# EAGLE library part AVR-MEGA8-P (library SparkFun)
MICROCONTROLLER 8 Kbytes FLASH 1 kbytes SRAM 512 bytes EEPROM USART 4-channel 10 bit ADC 2-channel 8 bit ADC

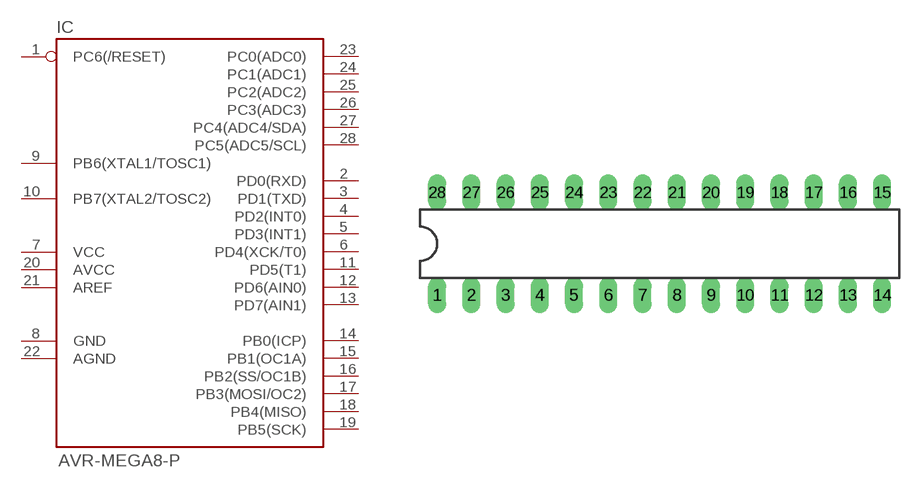
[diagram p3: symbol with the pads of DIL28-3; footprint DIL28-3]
Designator prefix IC

## AVR-MEGA8-P  [DIL28-3]
1  PC6(/RESET)
2  PD0(RXD)
3  PD1(TXD)
4  PD2(INT0)
5  PD3(INT1)
6  PD4(XCK/T0)
7  VCC
8  GND
9  PB6(XTAL1/TOSC1)
10  PB7(XTAL2/TOSC2)
11  PD5(T1)
12  PD6(AIN0)
13  PD7(AIN1)
14  PB0(ICP)
15  PB1(OC1A)
16  PB2(SS/OC1B)
17  PB3(MOSI/OC2)
18  PB4(MISO)
19  PB5(SCK)
20  AVCC
21  AREF
22  AGND
23  PC0(ADC0)
24  PC1(ADC1)
25  PC2(ADC2)
26  PC3(ADC3)
27  PC4(ADC4/SDA)
28  PC5(ADC5/SCL)

## Footprint DIL28-3 (pad centres in mm)
drill 0.813 long: 1 -13.97,-3.81; 2 -11.43,-3.81; 3 -8.89,-3.81; 4 -6.35,-3.81; 5 -3.81,-3.81; 6 -1.27,-3.81; 7 1.27,-3.81; 8 3.81,-3.81; 9 6.35,-3.81; 10 8.89,-3.81; 11 11.43,-3.81; 12 13.97,-3.81; 13 16.51,-3.81; 14 19.05,-3.81; 15 19.05,3.81; 16 16.51,3.81; 17 13.97,3.81; 18 11.43,3.81; 19 8.89,3.81; 20 6.35,3.81; 21 3.81,3.81; 22 1.27,3.81; 23 -1.27,3.81; 24 -3.81,3.81; 25 -6.35,3.81; 26 -8.89,3.81; 27 -11.43,3.81; 28 -13.97,3.81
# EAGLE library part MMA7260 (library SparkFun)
MMA7260Q Triple axis accelerometer from Freescale. Schematic element and footprint production proven. Center pad has reduced paste layer for solder short reduction. Spark Fun Electronics SKU : COM-00308

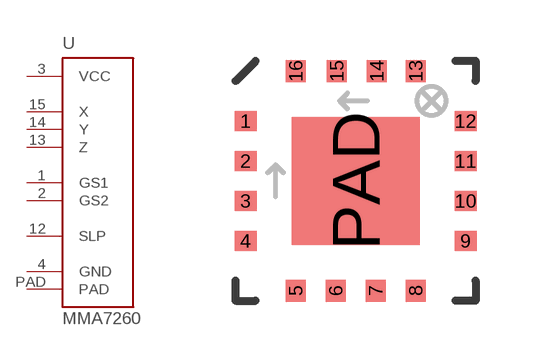
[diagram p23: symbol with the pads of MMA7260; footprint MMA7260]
Designator prefix U

## MMA7260  [MMA7260]
1  GS1
2  GS2
3  VCC
4  GND
12  SLP
13  Z
14  Y
15  X
PAD  PAD

## Footprint MMA7260 (pad centres in mm)
smd 0.55 x 0.5: 1 -2.75,1.5; 2 -2.75,0.5; 3 -2.75,-0.5; 4 -2.75,-1.5; 9 2.75,-1.5; 10 2.75,-0.5; 11 2.75,0.5; 12 2.75,1.5
smd 0.5 x 0.55: 5 -1.5,-2.75; 6 -0.5,-2.75; 7 0.5,-2.75; 8 1.5,-2.75; 13 1.5,2.75; 14 0.525,2.75; 15 -0.475,2.75; 16 -1.5,2.75
smd 3.2 x 3.2: PAD 0,0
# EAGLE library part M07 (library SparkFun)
Header 7 Standard 7-pin 0.1" header. Use with straight break away headers (SKU : PRT-00116), right angle break away headers (PRT-00553), swiss pins (PRT-00743), machine pins (PRT-00117), and female headers (PRT-00115). NOTES ON THE VARIANTS LOCK and LOCK_LONGPADS... This footprint was designed to help hold the alignment of a through-hole component (i.e. 7-pin header) while soldering it into place. You may notice that each hole has been shifted either up or down by 0.005 of an inch from it's more standard position (which is usually a perfectly straight line). This slight alteration caused the pins (the squares in the middle) to touch the edges of the holes. Because they are alternating, it causes a "brace" to hold the header in place. 0.005 has proven to be the perfect amount of "off-center" position when using our standard breakaway headers. Although looks a little odd when you look at the bare footprint, once you have a header in there, the alteration is very hard to notice. Also, if you push a header all the way into place, it is covered up entirely on the bottom side. This idea of altering the position of holes to aid alignment will be further integrated into the Sparkfun Library for other footprints. It can help hold any component with 3 or more connection pins.

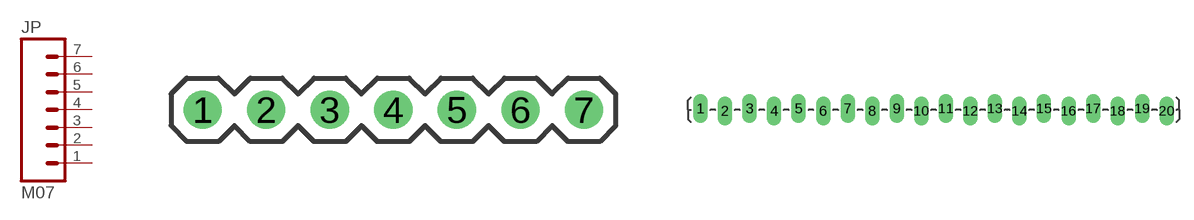
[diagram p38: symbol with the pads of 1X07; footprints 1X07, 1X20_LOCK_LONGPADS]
Designator prefix JP

## M07  [1X07]
1  1  pas
2  2  pas
3  3  pas
4  4  pas
5  5  pas
6  6  pas
7  7  pas

## M07LOCK_LONGPADS  [1X20_LOCK_LONGPADS]
Pads as for 1X07

## M07LOCK  [1X07_LOCK]
Pads as for 1X07

## Footprint 1X07 (pad centres in mm)
drill 1.016 round: 1 0,0; 2 2.54,0; 3 5.08,0; 4 7.62,0; 5 10.16,0; 6 12.7,0; 7 15.24,0

## Footprint 1X20_LOCK_LONGPADS (pad centres in mm)
drill 1.016 long: 1 0,0.127; 2 2.54,-0.127; 3 5.08,0.127; 4 7.62,-0.127; 5 10.16,0.127; 6 12.7,-0.127; 7 15.24,0.127; 8 17.78,-0.127; 9 20.32,0.127; 10 22.86,-0.127; 11 25.4,0.127; 12 27.94,-0.127; 13 30.48,0.127; 14 33.02,-0.127; 15 35.56,0.127; 16 38.1,-0.127; 17 40.64,0.127; 18 43.18,-0.127; 19 45.72,0.127; 20 48.26,-0.127

## Footprint 1X07_LOCK (pad centres in mm)
drill 1.016 round: 1 0,0.127; 2 2.54,-0.127; 3 5.08,0.127; 4 7.62,-0.127; 5 10.16,0.127; 6 12.7,-0.127; 7 15.24,0.127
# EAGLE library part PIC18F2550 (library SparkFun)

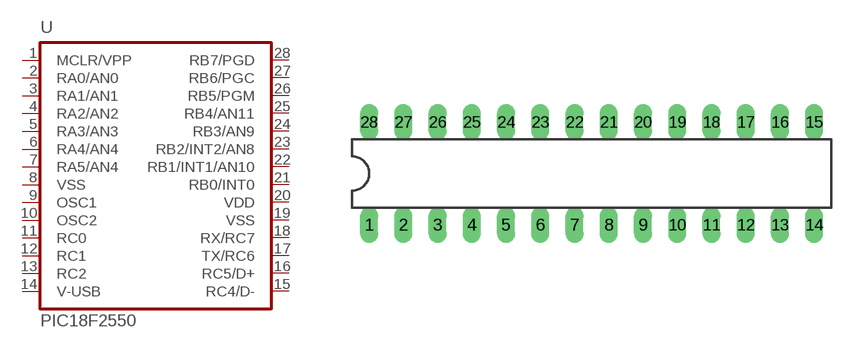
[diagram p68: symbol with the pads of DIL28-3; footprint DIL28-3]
Designator prefix -

## PIC18F2550  [DIL28-3]
1  MCLR/VPP
2  RA0/AN0
3  RA1/AN1
4  RA2/AN2
5  RA3/AN3
6  RA4/AN4
7  RA5/AN4
8  VSS  pwr
9  OSC1
10  OSC2
11  RC0
12  RC1
13  RC2
14  V-USB
15  RC4/D-
16  RC5/D+
17  TX/RC6
18  RX/RC7  in
19  VSS  pwr
20  VDD  pwr
21  RB0/INT0
22  RB1/INT1/AN10
23  RB2/INT2/AN8
24  RB3/AN9
25  RB4/AN11
26  RB5/PGM
27  RB6/PGC
28  RB7/PGD

## Footprint DIL28-3 (pad centres in mm)
drill 0.813 long: 1 -13.97,-3.81; 2 -11.43,-3.81; 3 -8.89,-3.81; 4 -6.35,-3.81; 5 -3.81,-3.81; 6 -1.27,-3.81; 7 1.27,-3.81; 8 3.81,-3.81; 9 6.35,-3.81; 10 8.89,-3.81; 11 11.43,-3.81; 12 13.97,-3.81; 13 16.51,-3.81; 14 19.05,-3.81; 15 19.05,3.81; 16 16.51,3.81; 17 13.97,3.81; 18 11.43,3.81; 19 8.89,3.81; 20 6.35,3.81; 21 3.81,3.81; 22 1.27,3.81; 23 -1.27,3.81; 24 -3.81,3.81; 25 -6.35,3.81; 26 -8.89,3.81; 27 -11.43,3.81; 28 -13.97,3.81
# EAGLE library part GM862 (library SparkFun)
GM862 Cellular Module with GPS Proven layout and schematic for GM862 cellular module with SiRF III GPS. Spark Fun Electronics SKU : CEL-07917

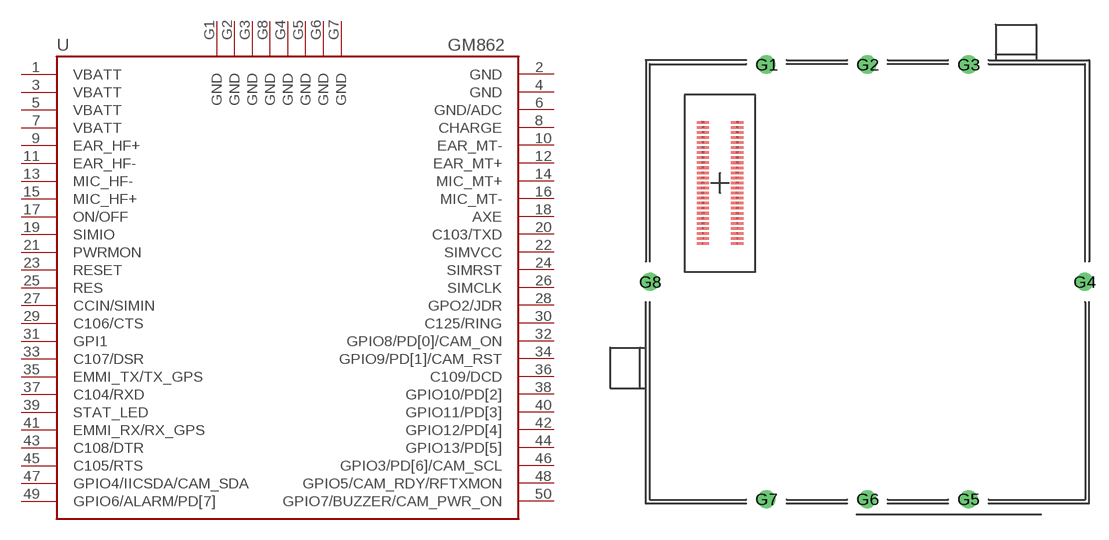
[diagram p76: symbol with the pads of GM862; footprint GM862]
Designator prefix -

## GM862GND  [GM862]
1  VBATT  pwr
2  GND  pwr
3  VBATT  pwr
4  GND  pwr
5  VBATT  pwr
6  GND/ADC  pwr
7  VBATT  pwr
8  CHARGE  in
9  EAR_HF+  out
10  EAR_MT-  out
11  EAR_HF-  out
12  EAR_MT+  out
13  MIC_HF-  in
14  MIC_MT+  in
15  MIC_HF+  in
16  MIC_MT-  in
17  ON/OFF  in
18  AXE  in
19  SIMIO
20  C103/TXD  in
21  PWRMON  out
22  SIMVCC  pwr
23  RESET  in
24  SIMRST  out
25  RES
26  SIMCLK  out
27  CCIN/SIMIN
28  GPO2/JDR  out
29  C106/CTS
30  C125/RING  out
31  GPI1  in
32  GPIO8/PD[0]/CAM_ON
33  C107/DSR  out
34  GPIO9/PD[1]/CAM_RST
35  EMMI_TX/TX_GPS  out
36  C109/DCD  out
37  C104/RXD  out
38  GPIO10/PD[2]
39  STAT_LED  out
40  GPIO11/PD[3]
41  EMMI_RX/RX_GPS  in
42  GPIO12/PD[4]
43  C108/DTR  in
44  GPIO13/PD[5]
45  C105/RTS  in
46  GPIO3/PD[6]/CAM_SCL
47  GPIO4/IICSDA/CAM_SDA
48  GPIO5/CAM_RDY/RFTXMON
49  GPIO6/ALARM/PD[7]
50  GPIO7/BUZZER/CAM_PWR_ON
G1  GND  pwr
G2  GND  pwr
G3  GND  pwr
G4  GND  pwr
G5  GND  pwr
G6  GND  pwr
G7  GND  pwr
G8  GND  pwr

## Footprint GM862 (pad centres in mm)
smd 1.2 x 0.25: 1 -12.898,3.788; 2 -16.298,3.792; 3 -12.898,4.288; 4 -16.298,4.292; 5 -12.898,4.788; 6 -16.298,4.792; 7 -12.898,5.288; 8 -16.298,5.292; 9 -12.898,5.788; 10 -16.298,5.792; 11 -12.899,6.287; 12 -16.298,6.292; 13 -12.898,6.788; 14 -16.298,6.792; 15 -12.898,7.288; 16 -16.298,7.292; 17 -12.898,7.788; 18 -16.298,7.792; 19 -12.898,8.288; 20 -16.298,8.292; 21 -12.898,8.788; 22 -16.298,8.792; 23 -12.898,9.288; 24 -16.298,9.292; 25 -12.898,9.788; 26 -16.298,9.792; 27 -12.898,10.288; 28 -16.298,10.292; 29 -12.898,10.788; 30 -16.298,10.792; 31 -12.898,11.288; 32 -16.298,11.292; 33 -12.898,11.788; 34 -16.298,11.792; 35 -12.898,12.288; 36 -16.298,12.292; 37 -12.898,12.788; 38 -16.298,12.792; 39 -12.898,13.288; 40 -16.298,13.292; 41 -12.898,13.788; 42 -16.298,13.792; 43 -12.898,14.288; 44 -16.298,14.292; 45 -12.898,14.788; 46 -16.298,14.792; 47 -12.898,15.288; 48 -16.298,15.292; 49 -12.898,15.788; 50 -16.298,15.792
drill 1.2 round: G1 -10,21.5; G2 0,21.5; G3 10,21.5; G4 21.5,0; G5 10,-21.5; G6 0,-21.5; G7 -10,-21.5; G8 -21.5,0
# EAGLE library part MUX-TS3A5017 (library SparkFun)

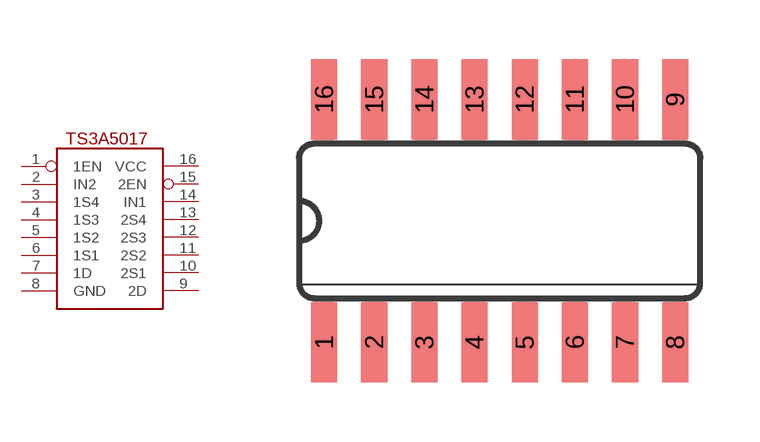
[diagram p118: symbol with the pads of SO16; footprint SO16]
Designator prefix -

## MUX-TS3A5017  [SO16]
1  1EN
2  IN2
3  1S4
4  1S3
5  1S2
6  1S1
7  1D
8  GND
9  2D
10  2S1
11  2S2
12  2S3
13  2S4
14  IN1
15  2EN
16  VCC

## Footprint SO16 (pad centres in mm)
Small Outline package 150 mil
smd 0.66 x 2.032: 1 -4.445,-3.073; 2 -3.175,-3.073; 3 -1.905,-3.073; 4 -0.635,-3.073; 5 0.635,-3.073; 6 1.905,-3.073; 7 3.175,-3.073; 8 4.445,-3.073; 9 4.445,3.073; 10 3.175,3.073; 11 1.905,3.073; 12 0.635,3.073; 13 -0.635,3.073; 14 -1.905,3.073; 15 -3.175,3.073; 16 -4.445,3.073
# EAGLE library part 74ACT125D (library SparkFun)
Quad Buffer with 3-State Outputs- ON Semi Conductor: Digikey P/N MC74ACT125DR2GOSTR-ND

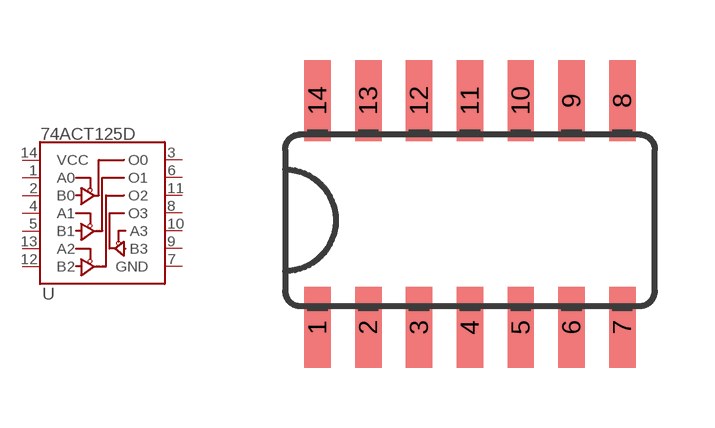
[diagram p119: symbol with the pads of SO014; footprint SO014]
Designator prefix -

## 74ACT125D  [SO014]
1  A0
2  B0
3  O0
4  A1
5  B1
6  O1
7  GND
8  O3
9  B3
10  A3
11  O2
12  B2
13  A2
14  VCC

## Footprint SO014 (pad centres in mm)
smd 0.66 x 2.032: 1 -3.175,-2.68; 2 -1.905,-2.68; 3 -0.635,-2.68; 4 0.635,-2.68; 5 1.905,-2.68; 6 3.175,-2.68; 7 4.445,-2.68; 8 4.445,2.997; 9 3.175,2.997; 10 1.905,2.997; 11 0.635,2.997; 12 -0.635,2.997; 13 -1.905,2.997; 14 -3.175,2.997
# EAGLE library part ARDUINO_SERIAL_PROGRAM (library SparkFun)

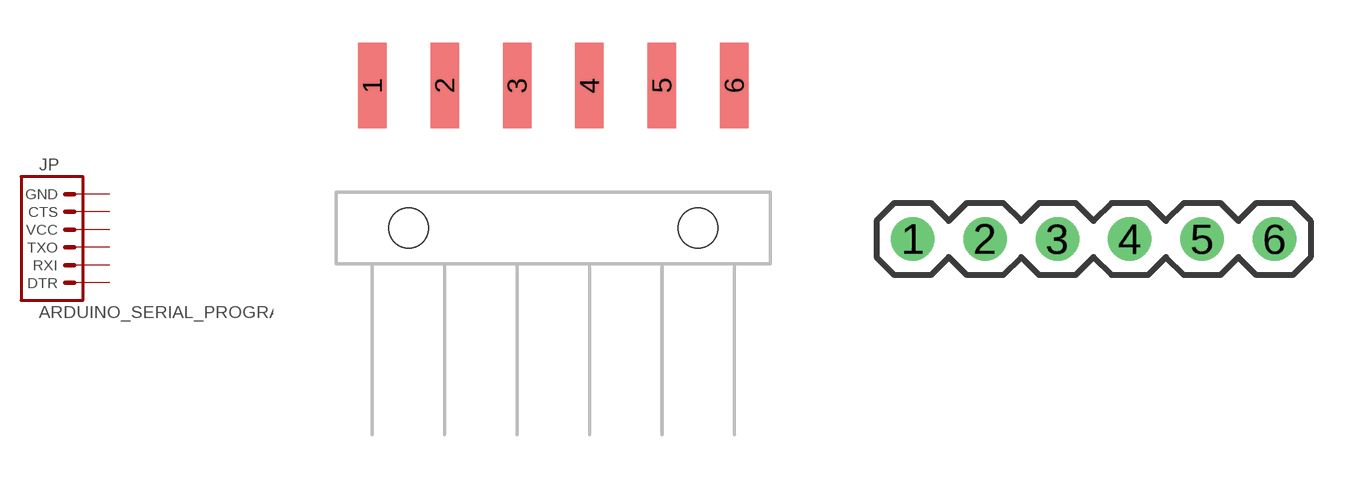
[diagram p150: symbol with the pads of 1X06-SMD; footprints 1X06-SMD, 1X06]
Designator prefix JP

## ARDUINO_SERIAL_PROGRAMSMD  [1X06-SMD]
1  DTR  pas
2  RXI  pas
3  TXO  pas
4  VCC  pas
5  CTS  pas
6  GND  pas

## ARDUINO_SERIAL_PROGRAMPTH  [1X06]
Pads as for 1X06-SMD

## Footprint 1X06-SMD (pad centres in mm)
smd 1 x 3: 1 -6.35,5; 2 -3.81,5; 3 -1.27,5; 4 1.27,5; 5 3.81,5; 6 6.35,5
hole 1.4 at -5.08,0
hole 1.4 at 5.08,0

## Footprint 1X06 (pad centres in mm)
drill 1.016 round: 1 0,0; 2 2.54,0; 3 5.08,0; 4 7.62,0; 5 10.16,0; 6 12.7,0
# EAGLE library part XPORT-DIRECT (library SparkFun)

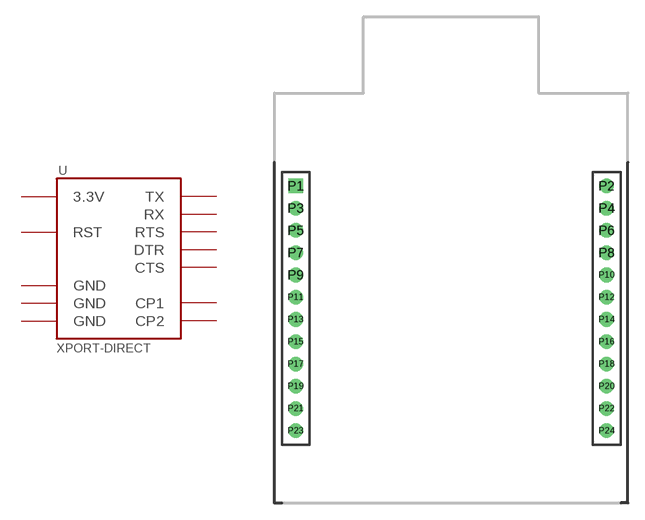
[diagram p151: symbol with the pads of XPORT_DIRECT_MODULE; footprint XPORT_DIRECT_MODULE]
Designator prefix -

## XPORT-DIRECT  [XPORT_DIRECT_MODULE]
P1  GND
P2  GND
P3  3.3V
P5  RST
P7  TX
P9  RX
P11  RTS
P13  DTR
P15  CTS
P21  CP2
P23  CP1
P24  GND

## Footprint XPORT_DIRECT_MODULE (pad centres in mm)
drill 0.8 square: P1 -13.97,9.3
drill 0.8 round: P2 13.97,9.3; P3 -13.97,7.3; P4 13.97,7.3; P5 -13.97,5.3; P6 13.97,5.3; P7 -13.97,3.3; P8 13.97,3.3; P9 -13.97,1.3; P10 13.97,1.3; P11 -13.97,-0.7; P12 13.97,-0.7; P13 -13.97,-2.7; P14 13.97,-2.7; P15 -13.97,-4.7; P16 13.97,-4.7; P17 -13.97,-6.7; P18 13.97,-6.7; P19 -13.97,-8.7; P20 13.97,-8.7; P21 -13.97,-10.7; P22 13.97,-10.7; P23 -13.97,-12.7; P24 13.97,-12.7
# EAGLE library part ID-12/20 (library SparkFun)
ID2, ID12, and ID20 Package

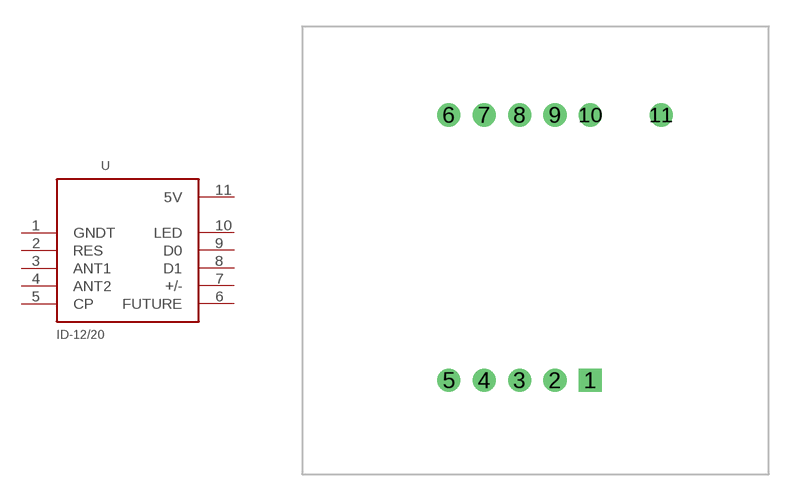
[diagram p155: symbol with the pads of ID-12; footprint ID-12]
Designator prefix -

## ID-12/20  [ID-12]
1  GNDT
2  RES
3  ANT1
4  ANT2
5  CP
6  FUTURE
7  +/-
8  D1
9  D0
10  LED
11  5V

## Footprint ID-12 (pad centres in mm)
ID12 Footprint (works with ID2, ID12, and ID20)
drill 0.8 square: 1 16.255,5.32
drill 0.8 round: 2 14.255,5.32; 3 12.255,5.32; 4 10.255,5.32; 5 8.255,5.32; 6 8.255,20.32; 7 10.255,20.32; 8 12.255,20.32; 9 14.255,20.32; 10 16.255,20.32; 11 20.255,20.32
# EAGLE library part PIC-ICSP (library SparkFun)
ISCP Programming connector for UAV, UBW Kit, etc.

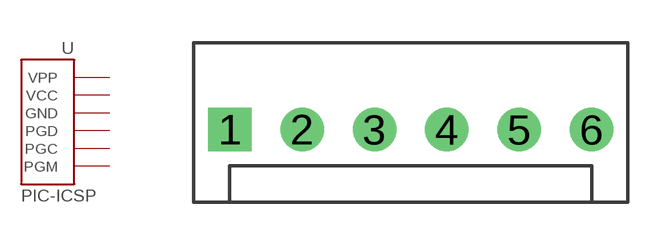
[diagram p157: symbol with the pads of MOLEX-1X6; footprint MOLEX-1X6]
Designator prefix -

## PIC-ICSP  [MOLEX-1X6]
1  PGM
2  PGC
3  PGD
4  GND
5  VCC
6  VPP

## Footprint MOLEX-1X6 (pad centres in mm)
drill 1.016 square: 1 0,0
drill 1.016 round: 2 2.54,0; 3 5.08,0; 4 7.62,0; 5 10.16,0; 6 12.7,0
